VERSION 5.7 ;
  NOWIREEXTENSIONATPIN ON ;
  DIVIDERCHAR "/" ;
  BUSBITCHARS "[]" ;
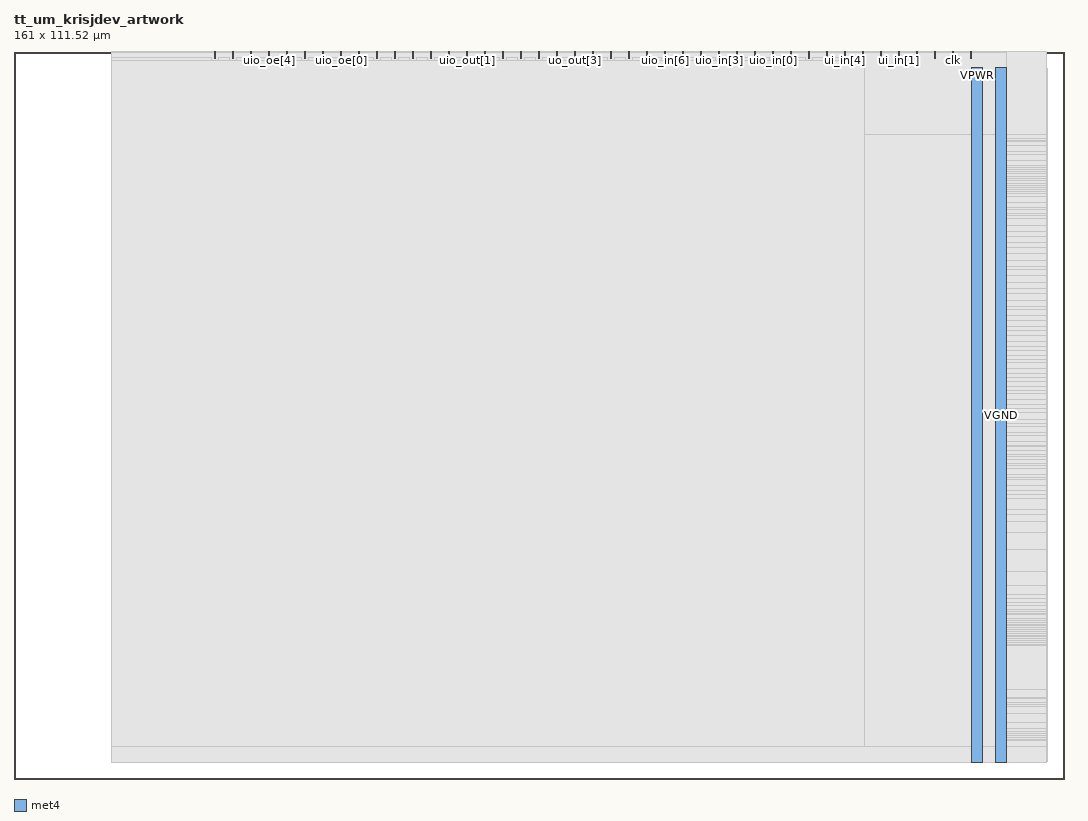
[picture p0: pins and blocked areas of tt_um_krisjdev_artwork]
MACRO tt_um_krisjdev_artwork
  CLASS BLOCK ;
  FOREIGN tt_um_krisjdev_artwork ;
  ORIGIN 0.000 0.000 ;
  SIZE 161.000 BY 111.520 ;
  PIN VGND
    DIRECTION INOUT ;
    USE GROUND ;
    PORT
      LAYER met4 ;
        RECT 150.540 2.480 152.140 109.040 ;
    END
  END VGND
  PIN VPWR
    DIRECTION INOUT ;
    USE POWER ;
    PORT
      LAYER met4 ;
        RECT 146.860 2.480 148.460 109.040 ;
    END
  END VPWR
  PIN clk
    DIRECTION INPUT ;
    USE SIGNAL ;
    PORT
      LAYER met4 ;
        RECT 143.830 110.520 144.130 111.520 ;
    END
  END clk
  PIN ena
    DIRECTION INPUT ;
    USE SIGNAL ;
    PORT
      LAYER met4 ;
        RECT 146.590 110.520 146.890 111.520 ;
    END
  END ena
  PIN rst_n
    DIRECTION INPUT ;
    USE SIGNAL ;
    PORT
      LAYER met4 ;
        RECT 141.070 110.520 141.370 111.520 ;
    END
  END rst_n
  PIN ui_in[0]
    DIRECTION INPUT ;
    USE SIGNAL ;
    PORT
      LAYER met4 ;
        RECT 138.310 110.520 138.610 111.520 ;
    END
  END ui_in[0]
  PIN ui_in[1]
    DIRECTION INPUT ;
    USE SIGNAL ;
    PORT
      LAYER met4 ;
        RECT 135.550 110.520 135.850 111.520 ;
    END
  END ui_in[1]
  PIN ui_in[2]
    DIRECTION INPUT ;
    USE SIGNAL ;
    PORT
      LAYER met4 ;
        RECT 132.790 110.520 133.090 111.520 ;
    END
  END ui_in[2]
  PIN ui_in[3]
    DIRECTION INPUT ;
    USE SIGNAL ;
    PORT
      LAYER met4 ;
        RECT 130.030 110.520 130.330 111.520 ;
    END
  END ui_in[3]
  PIN ui_in[4]
    DIRECTION INPUT ;
    USE SIGNAL ;
    PORT
      LAYER met4 ;
        RECT 127.270 110.520 127.570 111.520 ;
    END
  END ui_in[4]
  PIN ui_in[5]
    DIRECTION INPUT ;
    USE SIGNAL ;
    PORT
      LAYER met4 ;
        RECT 124.510 110.520 124.810 111.520 ;
    END
  END ui_in[5]
  PIN ui_in[6]
    DIRECTION INPUT ;
    USE SIGNAL ;
    PORT
      LAYER met4 ;
        RECT 121.750 110.520 122.050 111.520 ;
    END
  END ui_in[6]
  PIN ui_in[7]
    DIRECTION INPUT ;
    USE SIGNAL ;
    PORT
      LAYER met4 ;
        RECT 118.990 110.520 119.290 111.520 ;
    END
  END ui_in[7]
  PIN uio_in[0]
    DIRECTION INPUT ;
    USE SIGNAL ;
    PORT
      LAYER met4 ;
        RECT 116.230 110.520 116.530 111.520 ;
    END
  END uio_in[0]
  PIN uio_in[1]
    DIRECTION INPUT ;
    USE SIGNAL ;
    PORT
      LAYER met4 ;
        RECT 113.470 110.520 113.770 111.520 ;
    END
  END uio_in[1]
  PIN uio_in[2]
    DIRECTION INPUT ;
    USE SIGNAL ;
    PORT
      LAYER met4 ;
        RECT 110.710 110.520 111.010 111.520 ;
    END
  END uio_in[2]
  PIN uio_in[3]
    DIRECTION INPUT ;
    USE SIGNAL ;
    PORT
      LAYER met4 ;
        RECT 107.950 110.520 108.250 111.520 ;
    END
  END uio_in[3]
  PIN uio_in[4]
    DIRECTION INPUT ;
    USE SIGNAL ;
    PORT
      LAYER met4 ;
        RECT 105.190 110.520 105.490 111.520 ;
    END
  END uio_in[4]
  PIN uio_in[5]
    DIRECTION INPUT ;
    USE SIGNAL ;
    PORT
      LAYER met4 ;
        RECT 102.430 110.520 102.730 111.520 ;
    END
  END uio_in[5]
  PIN uio_in[6]
    DIRECTION INPUT ;
    USE SIGNAL ;
    PORT
      LAYER met4 ;
        RECT 99.670 110.520 99.970 111.520 ;
    END
  END uio_in[6]
  PIN uio_in[7]
    DIRECTION INPUT ;
    USE SIGNAL ;
    PORT
      LAYER met4 ;
        RECT 96.910 110.520 97.210 111.520 ;
    END
  END uio_in[7]
  PIN uio_oe[0]
    DIRECTION OUTPUT ;
    USE SIGNAL ;
    PORT
      LAYER met4 ;
        RECT 49.990 110.520 50.290 111.520 ;
    END
  END uio_oe[0]
  PIN uio_oe[1]
    DIRECTION OUTPUT ;
    USE SIGNAL ;
    PORT
      LAYER met4 ;
        RECT 47.230 110.520 47.530 111.520 ;
    END
  END uio_oe[1]
  PIN uio_oe[2]
    DIRECTION OUTPUT ;
    USE SIGNAL ;
    PORT
      LAYER met4 ;
        RECT 44.470 110.520 44.770 111.520 ;
    END
  END uio_oe[2]
  PIN uio_oe[3]
    DIRECTION OUTPUT ;
    USE SIGNAL ;
    PORT
      LAYER met4 ;
        RECT 41.710 110.520 42.010 111.520 ;
    END
  END uio_oe[3]
  PIN uio_oe[4]
    DIRECTION OUTPUT ;
    USE SIGNAL ;
    PORT
      LAYER met4 ;
        RECT 38.950 110.520 39.250 111.520 ;
    END
  END uio_oe[4]
  PIN uio_oe[5]
    DIRECTION OUTPUT ;
    USE SIGNAL ;
    PORT
      LAYER met4 ;
        RECT 36.190 110.520 36.490 111.520 ;
    END
  END uio_oe[5]
  PIN uio_oe[6]
    DIRECTION OUTPUT ;
    USE SIGNAL ;
    PORT
      LAYER met4 ;
        RECT 33.430 110.520 33.730 111.520 ;
    END
  END uio_oe[6]
  PIN uio_oe[7]
    DIRECTION OUTPUT ;
    USE SIGNAL ;
    PORT
      LAYER met4 ;
        RECT 30.670 110.520 30.970 111.520 ;
    END
  END uio_oe[7]
  PIN uio_out[0]
    DIRECTION OUTPUT ;
    USE SIGNAL ;
    PORT
      LAYER met4 ;
        RECT 72.070 110.520 72.370 111.520 ;
    END
  END uio_out[0]
  PIN uio_out[1]
    DIRECTION OUTPUT ;
    USE SIGNAL ;
    PORT
      LAYER met4 ;
        RECT 69.310 110.520 69.610 111.520 ;
    END
  END uio_out[1]
  PIN uio_out[2]
    DIRECTION OUTPUT ;
    USE SIGNAL ;
    PORT
      LAYER met4 ;
        RECT 66.550 110.520 66.850 111.520 ;
    END
  END uio_out[2]
  PIN uio_out[3]
    DIRECTION OUTPUT ;
    USE SIGNAL ;
    PORT
      LAYER met4 ;
        RECT 63.790 110.520 64.090 111.520 ;
    END
  END uio_out[3]
  PIN uio_out[4]
    DIRECTION OUTPUT ;
    USE SIGNAL ;
    PORT
      LAYER met4 ;
        RECT 61.030 110.520 61.330 111.520 ;
    END
  END uio_out[4]
  PIN uio_out[5]
    DIRECTION OUTPUT ;
    USE SIGNAL ;
    PORT
      LAYER met4 ;
        RECT 58.270 110.520 58.570 111.520 ;
    END
  END uio_out[5]
  PIN uio_out[6]
    DIRECTION OUTPUT ;
    USE SIGNAL ;
    PORT
      LAYER met4 ;
        RECT 55.510 110.520 55.810 111.520 ;
    END
  END uio_out[6]
  PIN uio_out[7]
    DIRECTION OUTPUT ;
    USE SIGNAL ;
    PORT
      LAYER met4 ;
        RECT 52.750 110.520 53.050 111.520 ;
    END
  END uio_out[7]
  PIN uo_out[0]
    DIRECTION OUTPUT ;
    USE SIGNAL ;
    PORT
      LAYER met4 ;
        RECT 94.150 110.520 94.450 111.520 ;
    END
  END uo_out[0]
  PIN uo_out[1]
    DIRECTION OUTPUT ;
    USE SIGNAL ;
    PORT
      LAYER met4 ;
        RECT 91.390 110.520 91.690 111.520 ;
    END
  END uo_out[1]
  PIN uo_out[2]
    DIRECTION OUTPUT ;
    USE SIGNAL ;
    PORT
      LAYER met4 ;
        RECT 88.630 110.520 88.930 111.520 ;
    END
  END uo_out[2]
  PIN uo_out[3]
    DIRECTION OUTPUT ;
    USE SIGNAL ;
    PORT
      LAYER met4 ;
        RECT 85.870 110.520 86.170 111.520 ;
    END
  END uo_out[3]
  PIN uo_out[4]
    DIRECTION OUTPUT ;
    USE SIGNAL ;
    PORT
      LAYER met4 ;
        RECT 83.110 110.520 83.410 111.520 ;
    END
  END uo_out[4]
  PIN uo_out[5]
    DIRECTION OUTPUT ;
    USE SIGNAL ;
    PORT
      LAYER met4 ;
        RECT 80.350 110.520 80.650 111.520 ;
    END
  END uo_out[5]
  PIN uo_out[6]
    DIRECTION OUTPUT ;
    USE SIGNAL ;
    PORT
      LAYER met4 ;
        RECT 77.590 110.520 77.890 111.520 ;
    END
  END uo_out[6]
  PIN uo_out[7]
    DIRECTION OUTPUT ;
    USE SIGNAL ;
    PORT
      LAYER met4 ;
        RECT 74.830 110.520 75.130 111.520 ;
    END
  END uo_out[7]
  OBS
      LAYER nwell ;
        RECT 140.570 2.635 158.430 108.990 ;
      LAYER li1 ;
        RECT 140.760 2.635 158.240 108.885 ;
      LAYER met1 ;
        RECT 15.000 98.800 158.240 111.480 ;
      LAYER met1 ;
        RECT 15.000 98.240 130.360 98.800 ;
      LAYER met1 ;
        RECT 130.360 98.240 158.240 98.800 ;
      LAYER met1 ;
        RECT 15.000 97.960 111.880 98.240 ;
      LAYER met1 ;
        RECT 111.880 97.960 158.240 98.240 ;
      LAYER met1 ;
        RECT 15.000 97.680 111.600 97.960 ;
      LAYER met1 ;
        RECT 111.600 97.680 158.240 97.960 ;
      LAYER met1 ;
        RECT 15.000 97.120 111.320 97.680 ;
      LAYER met1 ;
        RECT 111.320 97.120 158.240 97.680 ;
      LAYER met1 ;
        RECT 15.000 96.280 111.040 97.120 ;
      LAYER met1 ;
        RECT 111.040 96.280 158.240 97.120 ;
      LAYER met1 ;
        RECT 15.000 95.720 110.760 96.280 ;
      LAYER met1 ;
        RECT 110.760 95.720 158.240 96.280 ;
      LAYER met1 ;
        RECT 15.000 94.880 110.480 95.720 ;
      LAYER met1 ;
        RECT 110.480 94.880 158.240 95.720 ;
      LAYER met1 ;
        RECT 15.000 94.040 110.200 94.880 ;
      LAYER met1 ;
        RECT 110.200 94.040 158.240 94.880 ;
      LAYER met1 ;
        RECT 15.000 93.760 109.920 94.040 ;
      LAYER met1 ;
        RECT 109.920 93.760 158.240 94.040 ;
      LAYER met1 ;
        RECT 15.000 93.480 90.040 93.760 ;
      LAYER met1 ;
        RECT 90.040 93.480 158.240 93.760 ;
      LAYER met1 ;
        RECT 15.000 93.200 89.760 93.480 ;
      LAYER met1 ;
        RECT 89.760 93.200 158.240 93.480 ;
      LAYER met1 ;
        RECT 15.000 92.920 89.200 93.200 ;
      LAYER met1 ;
        RECT 89.200 92.920 158.240 93.200 ;
      LAYER met1 ;
        RECT 15.000 92.360 88.640 92.920 ;
      LAYER met1 ;
        RECT 88.640 92.360 158.240 92.920 ;
      LAYER met1 ;
        RECT 15.000 92.080 88.360 92.360 ;
      LAYER met1 ;
        RECT 88.360 92.080 158.240 92.360 ;
      LAYER met1 ;
        RECT 15.000 91.800 88.080 92.080 ;
      LAYER met1 ;
        RECT 88.080 91.800 158.240 92.080 ;
      LAYER met1 ;
        RECT 15.000 91.240 45.800 91.800 ;
      LAYER met1 ;
        RECT 45.800 91.240 158.240 91.800 ;
      LAYER met1 ;
        RECT 15.000 90.960 40.760 91.240 ;
      LAYER met1 ;
        RECT 40.760 90.960 158.240 91.240 ;
      LAYER met1 ;
        RECT 15.000 90.680 39.920 90.960 ;
      LAYER met1 ;
        RECT 39.920 90.680 158.240 90.960 ;
      LAYER met1 ;
        RECT 15.000 90.400 39.080 90.680 ;
      LAYER met1 ;
        RECT 39.080 90.400 158.240 90.680 ;
      LAYER met1 ;
        RECT 15.000 90.120 38.520 90.400 ;
      LAYER met1 ;
        RECT 38.520 90.120 158.240 90.400 ;
      LAYER met1 ;
        RECT 15.000 89.840 36.280 90.120 ;
      LAYER met1 ;
        RECT 36.280 89.840 158.240 90.120 ;
      LAYER met1 ;
        RECT 15.000 89.280 36.000 89.840 ;
      LAYER met1 ;
        RECT 36.000 89.280 158.240 89.840 ;
      LAYER met1 ;
        RECT 15.000 88.440 35.720 89.280 ;
      LAYER met1 ;
        RECT 35.720 88.440 158.240 89.280 ;
      LAYER met1 ;
        RECT 15.000 87.600 35.440 88.440 ;
      LAYER met1 ;
        RECT 35.440 87.600 158.240 88.440 ;
      LAYER met1 ;
        RECT 15.000 87.320 35.160 87.600 ;
      LAYER met1 ;
        RECT 35.160 87.320 158.240 87.600 ;
      LAYER met1 ;
        RECT 15.000 86.760 34.880 87.320 ;
      LAYER met1 ;
        RECT 34.880 86.760 158.240 87.320 ;
      LAYER met1 ;
        RECT 15.000 86.480 34.600 86.760 ;
      LAYER met1 ;
        RECT 34.600 86.480 158.240 86.760 ;
      LAYER met1 ;
        RECT 15.000 85.920 34.320 86.480 ;
      LAYER met1 ;
        RECT 34.320 85.920 158.240 86.480 ;
      LAYER met1 ;
        RECT 15.000 84.800 34.040 85.920 ;
      LAYER met1 ;
        RECT 34.040 84.800 158.240 85.920 ;
      LAYER met1 ;
        RECT 15.000 83.960 33.760 84.800 ;
      LAYER met1 ;
        RECT 33.760 83.960 158.240 84.800 ;
      LAYER met1 ;
        RECT 15.000 83.120 33.480 83.960 ;
      LAYER met1 ;
        RECT 33.480 83.120 158.240 83.960 ;
      LAYER met1 ;
        RECT 15.000 82.280 33.200 83.120 ;
      LAYER met1 ;
        RECT 33.200 82.280 158.240 83.120 ;
      LAYER met1 ;
        RECT 15.000 81.440 32.920 82.280 ;
      LAYER met1 ;
        RECT 32.920 81.440 158.240 82.280 ;
      LAYER met1 ;
        RECT 15.000 80.600 32.640 81.440 ;
      LAYER met1 ;
        RECT 32.640 80.600 158.240 81.440 ;
      LAYER met1 ;
        RECT 15.000 79.480 32.360 80.600 ;
      LAYER met1 ;
        RECT 32.360 79.480 158.240 80.600 ;
      LAYER met1 ;
        RECT 15.000 78.640 32.080 79.480 ;
      LAYER met1 ;
        RECT 32.080 78.640 158.240 79.480 ;
      LAYER met1 ;
        RECT 15.000 78.080 31.800 78.640 ;
      LAYER met1 ;
        RECT 31.800 78.080 158.240 78.640 ;
      LAYER met1 ;
        RECT 15.000 77.240 31.520 78.080 ;
      LAYER met1 ;
        RECT 31.520 77.240 158.240 78.080 ;
      LAYER met1 ;
        RECT 15.000 76.120 31.240 77.240 ;
      LAYER met1 ;
        RECT 31.240 76.120 158.240 77.240 ;
      LAYER met1 ;
        RECT 15.000 75.280 30.960 76.120 ;
      LAYER met1 ;
        RECT 30.960 75.280 158.240 76.120 ;
      LAYER met1 ;
        RECT 15.000 74.440 30.680 75.280 ;
      LAYER met1 ;
        RECT 30.680 74.440 158.240 75.280 ;
      LAYER met1 ;
        RECT 15.000 73.320 30.400 74.440 ;
      LAYER met1 ;
        RECT 30.400 73.320 158.240 74.440 ;
      LAYER met1 ;
        RECT 15.000 72.480 30.120 73.320 ;
      LAYER met1 ;
        RECT 30.120 72.480 158.240 73.320 ;
      LAYER met1 ;
        RECT 15.000 71.920 29.840 72.480 ;
      LAYER met1 ;
        RECT 29.840 71.920 158.240 72.480 ;
      LAYER met1 ;
        RECT 15.000 71.080 29.560 71.920 ;
      LAYER met1 ;
        RECT 29.560 71.080 158.240 71.920 ;
      LAYER met1 ;
        RECT 15.000 70.240 29.280 71.080 ;
      LAYER met1 ;
        RECT 29.280 70.240 158.240 71.080 ;
      LAYER met1 ;
        RECT 15.000 69.400 29.000 70.240 ;
      LAYER met1 ;
        RECT 29.000 69.400 158.240 70.240 ;
      LAYER met1 ;
        RECT 15.000 68.840 28.720 69.400 ;
      LAYER met1 ;
        RECT 28.720 68.840 158.240 69.400 ;
      LAYER met1 ;
        RECT 15.000 68.000 28.440 68.840 ;
      LAYER met1 ;
        RECT 28.440 68.000 158.240 68.840 ;
      LAYER met1 ;
        RECT 15.000 67.160 28.160 68.000 ;
      LAYER met1 ;
        RECT 28.160 67.160 158.240 68.000 ;
      LAYER met1 ;
        RECT 15.000 66.320 27.880 67.160 ;
      LAYER met1 ;
        RECT 27.880 66.320 158.240 67.160 ;
      LAYER met1 ;
        RECT 15.000 65.760 27.600 66.320 ;
      LAYER met1 ;
        RECT 27.600 65.760 158.240 66.320 ;
      LAYER met1 ;
        RECT 15.000 64.920 27.320 65.760 ;
      LAYER met1 ;
        RECT 27.320 64.920 158.240 65.760 ;
      LAYER met1 ;
        RECT 15.000 64.360 27.040 64.920 ;
      LAYER met1 ;
        RECT 27.040 64.360 158.240 64.920 ;
      LAYER met1 ;
        RECT 15.000 63.800 26.760 64.360 ;
      LAYER met1 ;
        RECT 26.760 63.800 158.240 64.360 ;
      LAYER met1 ;
        RECT 15.000 62.960 26.480 63.800 ;
      LAYER met1 ;
        RECT 26.480 62.960 158.240 63.800 ;
      LAYER met1 ;
        RECT 15.000 62.120 26.200 62.960 ;
      LAYER met1 ;
        RECT 26.200 62.120 158.240 62.960 ;
      LAYER met1 ;
        RECT 15.000 61.560 25.920 62.120 ;
      LAYER met1 ;
        RECT 25.920 61.560 158.240 62.120 ;
      LAYER met1 ;
        RECT 15.000 61.000 25.640 61.560 ;
      LAYER met1 ;
        RECT 25.640 61.000 158.240 61.560 ;
      LAYER met1 ;
        RECT 15.000 60.160 25.360 61.000 ;
      LAYER met1 ;
        RECT 25.360 60.160 158.240 61.000 ;
      LAYER met1 ;
        RECT 15.000 59.600 25.080 60.160 ;
      LAYER met1 ;
        RECT 25.080 59.600 158.240 60.160 ;
      LAYER met1 ;
        RECT 15.000 59.040 24.800 59.600 ;
      LAYER met1 ;
        RECT 24.800 59.040 158.240 59.600 ;
      LAYER met1 ;
        RECT 15.000 58.200 24.520 59.040 ;
      LAYER met1 ;
        RECT 24.520 58.200 158.240 59.040 ;
      LAYER met1 ;
        RECT 15.000 57.360 24.240 58.200 ;
      LAYER met1 ;
        RECT 24.240 57.360 158.240 58.200 ;
      LAYER met1 ;
        RECT 15.000 56.800 23.960 57.360 ;
      LAYER met1 ;
        RECT 23.960 56.800 158.240 57.360 ;
      LAYER met1 ;
        RECT 15.000 56.240 23.680 56.800 ;
      LAYER met1 ;
        RECT 23.680 56.240 158.240 56.800 ;
      LAYER met1 ;
        RECT 15.000 55.120 23.400 56.240 ;
      LAYER met1 ;
        RECT 23.400 55.120 158.240 56.240 ;
      LAYER met1 ;
        RECT 15.000 54.560 23.120 55.120 ;
      LAYER met1 ;
        RECT 23.120 54.560 158.240 55.120 ;
      LAYER met1 ;
        RECT 15.000 54.000 22.840 54.560 ;
      LAYER met1 ;
        RECT 22.840 54.000 158.240 54.560 ;
      LAYER met1 ;
        RECT 15.000 53.160 22.560 54.000 ;
      LAYER met1 ;
        RECT 22.560 53.160 158.240 54.000 ;
      LAYER met1 ;
        RECT 15.000 52.600 22.280 53.160 ;
      LAYER met1 ;
        RECT 22.280 52.600 158.240 53.160 ;
      LAYER met1 ;
        RECT 15.000 51.760 22.000 52.600 ;
      LAYER met1 ;
        RECT 22.000 51.760 158.240 52.600 ;
      LAYER met1 ;
        RECT 15.000 51.200 21.720 51.760 ;
      LAYER met1 ;
        RECT 21.720 51.200 158.240 51.760 ;
      LAYER met1 ;
        RECT 15.000 50.920 21.440 51.200 ;
      LAYER met1 ;
        RECT 21.440 50.920 158.240 51.200 ;
      LAYER met1 ;
        RECT 15.000 50.360 21.160 50.920 ;
      LAYER met1 ;
        RECT 21.160 50.360 158.240 50.920 ;
      LAYER met1 ;
        RECT 15.000 49.800 20.880 50.360 ;
      LAYER met1 ;
        RECT 20.880 49.800 158.240 50.360 ;
      LAYER met1 ;
        RECT 15.000 49.520 20.600 49.800 ;
      LAYER met1 ;
        RECT 20.600 49.520 158.240 49.800 ;
      LAYER met1 ;
        RECT 15.000 48.960 20.320 49.520 ;
      LAYER met1 ;
        RECT 20.320 48.960 158.240 49.520 ;
      LAYER met1 ;
        RECT 15.000 48.400 20.040 48.960 ;
      LAYER met1 ;
        RECT 20.040 48.400 158.240 48.960 ;
      LAYER met1 ;
        RECT 15.000 48.120 19.760 48.400 ;
      LAYER met1 ;
        RECT 19.760 48.120 158.240 48.400 ;
      LAYER met1 ;
        RECT 15.000 47.560 19.480 48.120 ;
      LAYER met1 ;
        RECT 19.480 47.560 158.240 48.120 ;
      LAYER met1 ;
        RECT 15.000 46.720 19.200 47.560 ;
      LAYER met1 ;
        RECT 19.200 46.720 158.240 47.560 ;
      LAYER met1 ;
        RECT 15.000 46.160 18.920 46.720 ;
      LAYER met1 ;
        RECT 18.920 46.160 158.240 46.720 ;
      LAYER met1 ;
        RECT 15.000 45.880 18.640 46.160 ;
      LAYER met1 ;
        RECT 18.640 45.880 158.240 46.160 ;
      LAYER met1 ;
        RECT 15.000 45.040 18.360 45.880 ;
      LAYER met1 ;
        RECT 18.360 45.040 158.240 45.880 ;
      LAYER met1 ;
        RECT 15.000 44.200 18.080 45.040 ;
      LAYER met1 ;
        RECT 18.080 44.200 158.240 45.040 ;
      LAYER met1 ;
        RECT 15.000 43.640 17.800 44.200 ;
      LAYER met1 ;
        RECT 17.800 43.640 158.240 44.200 ;
      LAYER met1 ;
        RECT 15.000 43.080 17.520 43.640 ;
      LAYER met1 ;
        RECT 17.520 43.080 158.240 43.640 ;
      LAYER met1 ;
        RECT 15.000 41.400 17.240 43.080 ;
      LAYER met1 ;
        RECT 17.240 41.400 158.240 43.080 ;
      LAYER met1 ;
        RECT 15.000 40.560 16.960 41.400 ;
      LAYER met1 ;
        RECT 16.960 40.560 158.240 41.400 ;
      LAYER met1 ;
        RECT 15.000 39.440 16.680 40.560 ;
      LAYER met1 ;
        RECT 16.680 39.440 158.240 40.560 ;
      LAYER met1 ;
        RECT 15.000 37.760 16.400 39.440 ;
      LAYER met1 ;
        RECT 16.400 37.760 158.240 39.440 ;
      LAYER met1 ;
        RECT 15.000 35.240 16.120 37.760 ;
      LAYER met1 ;
        RECT 16.120 35.240 158.240 37.760 ;
      LAYER met1 ;
        RECT 15.000 31.880 15.840 35.240 ;
      LAYER met1 ;
        RECT 15.840 31.880 158.240 35.240 ;
      LAYER met1 ;
        RECT 15.000 29.640 16.120 31.880 ;
      LAYER met1 ;
        RECT 16.120 29.640 158.240 31.880 ;
      LAYER met1 ;
        RECT 15.000 28.240 16.400 29.640 ;
      LAYER met1 ;
        RECT 16.400 28.240 158.240 29.640 ;
      LAYER met1 ;
        RECT 15.000 27.680 16.680 28.240 ;
      LAYER met1 ;
        RECT 16.680 27.680 158.240 28.240 ;
      LAYER met1 ;
        RECT 15.000 27.120 16.960 27.680 ;
      LAYER met1 ;
        RECT 16.960 27.120 158.240 27.680 ;
      LAYER met1 ;
        RECT 15.000 26.560 17.240 27.120 ;
      LAYER met1 ;
        RECT 17.240 26.560 158.240 27.120 ;
      LAYER met1 ;
        RECT 15.000 26.000 17.520 26.560 ;
      LAYER met1 ;
        RECT 17.520 26.000 158.240 26.560 ;
      LAYER met1 ;
        RECT 15.000 25.720 17.800 26.000 ;
      LAYER met1 ;
        RECT 17.800 25.720 158.240 26.000 ;
      LAYER met1 ;
        RECT 15.000 25.440 18.080 25.720 ;
      LAYER met1 ;
        RECT 18.080 25.440 158.240 25.720 ;
      LAYER met1 ;
        RECT 15.000 25.160 18.360 25.440 ;
      LAYER met1 ;
        RECT 18.360 25.160 158.240 25.440 ;
      LAYER met1 ;
        RECT 15.000 24.600 18.640 25.160 ;
      LAYER met1 ;
        RECT 18.640 24.600 158.240 25.160 ;
      LAYER met1 ;
        RECT 15.000 24.320 18.920 24.600 ;
      LAYER met1 ;
        RECT 18.920 24.320 158.240 24.600 ;
      LAYER met1 ;
        RECT 15.000 24.040 19.200 24.320 ;
      LAYER met1 ;
        RECT 19.200 24.040 158.240 24.320 ;
      LAYER met1 ;
        RECT 15.000 23.760 19.480 24.040 ;
      LAYER met1 ;
        RECT 19.480 23.760 158.240 24.040 ;
      LAYER met1 ;
        RECT 15.000 23.480 19.760 23.760 ;
      LAYER met1 ;
        RECT 19.760 23.480 158.240 23.760 ;
      LAYER met1 ;
        RECT 15.000 23.200 20.040 23.480 ;
      LAYER met1 ;
        RECT 20.040 23.200 158.240 23.480 ;
      LAYER met1 ;
        RECT 15.000 22.920 20.320 23.200 ;
      LAYER met1 ;
        RECT 20.320 22.920 158.240 23.200 ;
      LAYER met1 ;
        RECT 15.000 22.640 20.600 22.920 ;
      LAYER met1 ;
        RECT 20.600 22.640 158.240 22.920 ;
      LAYER met1 ;
        RECT 15.000 22.360 21.160 22.640 ;
      LAYER met1 ;
        RECT 21.160 22.360 158.240 22.640 ;
      LAYER met1 ;
        RECT 15.000 22.080 21.440 22.360 ;
      LAYER met1 ;
        RECT 21.440 22.080 158.240 22.360 ;
      LAYER met1 ;
        RECT 15.000 21.800 21.720 22.080 ;
      LAYER met1 ;
        RECT 21.720 21.800 158.240 22.080 ;
      LAYER met1 ;
        RECT 15.000 21.520 22.000 21.800 ;
      LAYER met1 ;
        RECT 22.000 21.520 158.240 21.800 ;
      LAYER met1 ;
        RECT 15.000 21.240 22.280 21.520 ;
      LAYER met1 ;
        RECT 22.280 21.240 158.240 21.520 ;
      LAYER met1 ;
        RECT 15.000 20.960 22.840 21.240 ;
      LAYER met1 ;
        RECT 22.840 20.960 158.240 21.240 ;
      LAYER met1 ;
        RECT 15.000 20.680 23.400 20.960 ;
      LAYER met1 ;
        RECT 23.400 20.680 158.240 20.960 ;
      LAYER met1 ;
        RECT 15.000 20.400 24.800 20.680 ;
      LAYER met1 ;
        RECT 24.800 20.400 158.240 20.680 ;
      LAYER met1 ;
        RECT 15.000 13.680 26.480 20.400 ;
      LAYER met1 ;
        RECT 26.480 13.680 158.240 20.400 ;
      LAYER met1 ;
        RECT 15.000 12.560 26.760 13.680 ;
      LAYER met1 ;
        RECT 26.760 12.560 158.240 13.680 ;
      LAYER met1 ;
        RECT 15.000 12.280 27.040 12.560 ;
      LAYER met1 ;
        RECT 27.040 12.280 158.240 12.560 ;
      LAYER met1 ;
        RECT 15.000 11.720 27.320 12.280 ;
      LAYER met1 ;
        RECT 27.320 11.720 158.240 12.280 ;
      LAYER met1 ;
        RECT 15.000 11.440 28.160 11.720 ;
      LAYER met1 ;
        RECT 28.160 11.440 158.240 11.720 ;
      LAYER met1 ;
        RECT 15.000 11.160 81.640 11.440 ;
      LAYER met1 ;
        RECT 81.640 11.160 158.240 11.440 ;
      LAYER met1 ;
        RECT 15.000 10.040 81.360 11.160 ;
      LAYER met1 ;
        RECT 81.360 10.040 158.240 11.160 ;
      LAYER met1 ;
        RECT 15.000 8.640 81.080 10.040 ;
      LAYER met1 ;
        RECT 81.080 8.640 158.240 10.040 ;
      LAYER met1 ;
        RECT 15.000 7.800 81.360 8.640 ;
      LAYER met1 ;
        RECT 81.360 7.800 158.240 8.640 ;
      LAYER met1 ;
        RECT 15.000 7.240 81.640 7.800 ;
      LAYER met1 ;
        RECT 81.640 7.240 158.240 7.800 ;
      LAYER met1 ;
        RECT 15.000 6.960 81.920 7.240 ;
      LAYER met1 ;
        RECT 81.920 6.960 158.240 7.240 ;
      LAYER met1 ;
        RECT 15.000 6.680 82.480 6.960 ;
      LAYER met1 ;
        RECT 82.480 6.680 158.240 6.960 ;
      LAYER met1 ;
        RECT 15.000 6.400 83.320 6.680 ;
      LAYER met1 ;
        RECT 83.320 6.400 158.240 6.680 ;
      LAYER met1 ;
        RECT 15.000 6.120 120.560 6.400 ;
      LAYER met1 ;
        RECT 120.560 6.120 158.240 6.400 ;
      LAYER met1 ;
        RECT 15.000 5.840 121.120 6.120 ;
      LAYER met1 ;
        RECT 121.120 5.840 158.240 6.120 ;
      LAYER met1 ;
        RECT 15.000 5.000 130.360 5.840 ;
      LAYER met1 ;
        RECT 130.360 5.000 158.240 5.840 ;
        RECT 15.000 2.480 158.240 5.000 ;
      LAYER met2 ;
        RECT 15.000 98.800 152.110 111.510 ;
      LAYER met2 ;
        RECT 15.000 98.240 130.360 98.800 ;
      LAYER met2 ;
        RECT 130.360 98.240 152.110 98.800 ;
      LAYER met2 ;
        RECT 15.000 97.960 111.880 98.240 ;
      LAYER met2 ;
        RECT 111.880 97.960 152.110 98.240 ;
      LAYER met2 ;
        RECT 15.000 97.680 111.600 97.960 ;
      LAYER met2 ;
        RECT 111.600 97.680 152.110 97.960 ;
      LAYER met2 ;
        RECT 15.000 97.120 111.320 97.680 ;
      LAYER met2 ;
        RECT 111.320 97.120 152.110 97.680 ;
      LAYER met2 ;
        RECT 15.000 96.280 111.040 97.120 ;
      LAYER met2 ;
        RECT 111.040 96.280 152.110 97.120 ;
      LAYER met2 ;
        RECT 15.000 95.720 110.760 96.280 ;
      LAYER met2 ;
        RECT 110.760 95.720 152.110 96.280 ;
      LAYER met2 ;
        RECT 15.000 94.880 110.480 95.720 ;
      LAYER met2 ;
        RECT 110.480 94.880 152.110 95.720 ;
      LAYER met2 ;
        RECT 15.000 94.040 110.200 94.880 ;
      LAYER met2 ;
        RECT 110.200 94.040 152.110 94.880 ;
      LAYER met2 ;
        RECT 15.000 93.760 109.920 94.040 ;
      LAYER met2 ;
        RECT 109.920 93.760 152.110 94.040 ;
      LAYER met2 ;
        RECT 15.000 93.480 90.040 93.760 ;
      LAYER met2 ;
        RECT 90.040 93.480 152.110 93.760 ;
      LAYER met2 ;
        RECT 15.000 93.200 89.760 93.480 ;
      LAYER met2 ;
        RECT 89.760 93.200 152.110 93.480 ;
      LAYER met2 ;
        RECT 15.000 92.920 89.200 93.200 ;
      LAYER met2 ;
        RECT 89.200 92.920 152.110 93.200 ;
      LAYER met2 ;
        RECT 15.000 92.360 88.640 92.920 ;
      LAYER met2 ;
        RECT 88.640 92.360 152.110 92.920 ;
      LAYER met2 ;
        RECT 15.000 92.080 88.360 92.360 ;
      LAYER met2 ;
        RECT 88.360 92.080 152.110 92.360 ;
      LAYER met2 ;
        RECT 15.000 91.800 88.080 92.080 ;
      LAYER met2 ;
        RECT 88.080 91.800 152.110 92.080 ;
      LAYER met2 ;
        RECT 15.000 91.240 45.800 91.800 ;
      LAYER met2 ;
        RECT 45.800 91.240 152.110 91.800 ;
      LAYER met2 ;
        RECT 15.000 90.960 40.760 91.240 ;
      LAYER met2 ;
        RECT 40.760 90.960 152.110 91.240 ;
      LAYER met2 ;
        RECT 15.000 90.680 39.920 90.960 ;
      LAYER met2 ;
        RECT 39.920 90.680 152.110 90.960 ;
      LAYER met2 ;
        RECT 15.000 90.400 39.080 90.680 ;
      LAYER met2 ;
        RECT 39.080 90.400 152.110 90.680 ;
      LAYER met2 ;
        RECT 15.000 90.120 38.520 90.400 ;
      LAYER met2 ;
        RECT 38.520 90.120 152.110 90.400 ;
      LAYER met2 ;
        RECT 15.000 89.840 36.280 90.120 ;
      LAYER met2 ;
        RECT 36.280 89.840 152.110 90.120 ;
      LAYER met2 ;
        RECT 15.000 89.280 36.000 89.840 ;
      LAYER met2 ;
        RECT 36.000 89.280 152.110 89.840 ;
      LAYER met2 ;
        RECT 15.000 88.440 35.720 89.280 ;
      LAYER met2 ;
        RECT 35.720 88.440 152.110 89.280 ;
      LAYER met2 ;
        RECT 15.000 87.600 35.440 88.440 ;
      LAYER met2 ;
        RECT 35.440 87.600 152.110 88.440 ;
      LAYER met2 ;
        RECT 15.000 87.320 35.160 87.600 ;
      LAYER met2 ;
        RECT 35.160 87.320 152.110 87.600 ;
      LAYER met2 ;
        RECT 15.000 86.760 34.880 87.320 ;
      LAYER met2 ;
        RECT 34.880 86.760 152.110 87.320 ;
      LAYER met2 ;
        RECT 15.000 86.480 34.600 86.760 ;
      LAYER met2 ;
        RECT 34.600 86.480 152.110 86.760 ;
      LAYER met2 ;
        RECT 15.000 85.920 34.320 86.480 ;
      LAYER met2 ;
        RECT 34.320 85.920 152.110 86.480 ;
      LAYER met2 ;
        RECT 15.000 84.800 34.040 85.920 ;
      LAYER met2 ;
        RECT 34.040 84.800 152.110 85.920 ;
      LAYER met2 ;
        RECT 15.000 83.960 33.760 84.800 ;
      LAYER met2 ;
        RECT 33.760 83.960 152.110 84.800 ;
      LAYER met2 ;
        RECT 15.000 83.120 33.480 83.960 ;
      LAYER met2 ;
        RECT 33.480 83.120 152.110 83.960 ;
      LAYER met2 ;
        RECT 15.000 82.280 33.200 83.120 ;
      LAYER met2 ;
        RECT 33.200 82.280 152.110 83.120 ;
      LAYER met2 ;
        RECT 15.000 81.440 32.920 82.280 ;
      LAYER met2 ;
        RECT 32.920 81.440 152.110 82.280 ;
      LAYER met2 ;
        RECT 15.000 80.600 32.640 81.440 ;
      LAYER met2 ;
        RECT 32.640 80.600 152.110 81.440 ;
      LAYER met2 ;
        RECT 15.000 79.480 32.360 80.600 ;
      LAYER met2 ;
        RECT 32.360 79.480 152.110 80.600 ;
      LAYER met2 ;
        RECT 15.000 78.640 32.080 79.480 ;
      LAYER met2 ;
        RECT 32.080 78.640 152.110 79.480 ;
      LAYER met2 ;
        RECT 15.000 78.080 31.800 78.640 ;
      LAYER met2 ;
        RECT 31.800 78.080 152.110 78.640 ;
      LAYER met2 ;
        RECT 15.000 77.240 31.520 78.080 ;
      LAYER met2 ;
        RECT 31.520 77.240 152.110 78.080 ;
      LAYER met2 ;
        RECT 15.000 76.120 31.240 77.240 ;
      LAYER met2 ;
        RECT 31.240 76.120 152.110 77.240 ;
      LAYER met2 ;
        RECT 15.000 75.280 30.960 76.120 ;
      LAYER met2 ;
        RECT 30.960 75.280 152.110 76.120 ;
      LAYER met2 ;
        RECT 15.000 74.440 30.680 75.280 ;
      LAYER met2 ;
        RECT 30.680 74.440 152.110 75.280 ;
      LAYER met2 ;
        RECT 15.000 73.320 30.400 74.440 ;
      LAYER met2 ;
        RECT 30.400 73.320 152.110 74.440 ;
      LAYER met2 ;
        RECT 15.000 72.480 30.120 73.320 ;
      LAYER met2 ;
        RECT 30.120 72.480 152.110 73.320 ;
      LAYER met2 ;
        RECT 15.000 71.920 29.840 72.480 ;
      LAYER met2 ;
        RECT 29.840 71.920 152.110 72.480 ;
      LAYER met2 ;
        RECT 15.000 71.080 29.560 71.920 ;
      LAYER met2 ;
        RECT 29.560 71.080 152.110 71.920 ;
      LAYER met2 ;
        RECT 15.000 70.240 29.280 71.080 ;
      LAYER met2 ;
        RECT 29.280 70.240 152.110 71.080 ;
      LAYER met2 ;
        RECT 15.000 69.400 29.000 70.240 ;
      LAYER met2 ;
        RECT 29.000 69.400 152.110 70.240 ;
      LAYER met2 ;
        RECT 15.000 68.840 28.720 69.400 ;
      LAYER met2 ;
        RECT 28.720 68.840 152.110 69.400 ;
      LAYER met2 ;
        RECT 15.000 68.000 28.440 68.840 ;
      LAYER met2 ;
        RECT 28.440 68.000 152.110 68.840 ;
      LAYER met2 ;
        RECT 15.000 67.160 28.160 68.000 ;
      LAYER met2 ;
        RECT 28.160 67.160 152.110 68.000 ;
      LAYER met2 ;
        RECT 15.000 66.320 27.880 67.160 ;
      LAYER met2 ;
        RECT 27.880 66.320 152.110 67.160 ;
      LAYER met2 ;
        RECT 15.000 65.760 27.600 66.320 ;
      LAYER met2 ;
        RECT 27.600 65.760 152.110 66.320 ;
      LAYER met2 ;
        RECT 15.000 64.920 27.320 65.760 ;
      LAYER met2 ;
        RECT 27.320 64.920 152.110 65.760 ;
      LAYER met2 ;
        RECT 15.000 64.360 27.040 64.920 ;
      LAYER met2 ;
        RECT 27.040 64.360 152.110 64.920 ;
      LAYER met2 ;
        RECT 15.000 63.800 26.760 64.360 ;
      LAYER met2 ;
        RECT 26.760 63.800 152.110 64.360 ;
      LAYER met2 ;
        RECT 15.000 62.960 26.480 63.800 ;
      LAYER met2 ;
        RECT 26.480 62.960 152.110 63.800 ;
      LAYER met2 ;
        RECT 15.000 62.120 26.200 62.960 ;
      LAYER met2 ;
        RECT 26.200 62.120 152.110 62.960 ;
      LAYER met2 ;
        RECT 15.000 61.560 25.920 62.120 ;
      LAYER met2 ;
        RECT 25.920 61.560 152.110 62.120 ;
      LAYER met2 ;
        RECT 15.000 61.000 25.640 61.560 ;
      LAYER met2 ;
        RECT 25.640 61.000 152.110 61.560 ;
      LAYER met2 ;
        RECT 15.000 60.160 25.360 61.000 ;
      LAYER met2 ;
        RECT 25.360 60.160 152.110 61.000 ;
      LAYER met2 ;
        RECT 15.000 59.600 25.080 60.160 ;
      LAYER met2 ;
        RECT 25.080 59.600 152.110 60.160 ;
      LAYER met2 ;
        RECT 15.000 59.040 24.800 59.600 ;
      LAYER met2 ;
        RECT 24.800 59.040 152.110 59.600 ;
      LAYER met2 ;
        RECT 15.000 58.200 24.520 59.040 ;
      LAYER met2 ;
        RECT 24.520 58.200 152.110 59.040 ;
      LAYER met2 ;
        RECT 15.000 57.360 24.240 58.200 ;
      LAYER met2 ;
        RECT 24.240 57.360 152.110 58.200 ;
      LAYER met2 ;
        RECT 15.000 56.800 23.960 57.360 ;
      LAYER met2 ;
        RECT 23.960 56.800 152.110 57.360 ;
      LAYER met2 ;
        RECT 15.000 56.240 23.680 56.800 ;
      LAYER met2 ;
        RECT 23.680 56.240 152.110 56.800 ;
      LAYER met2 ;
        RECT 15.000 55.120 23.400 56.240 ;
      LAYER met2 ;
        RECT 23.400 55.120 152.110 56.240 ;
      LAYER met2 ;
        RECT 15.000 54.560 23.120 55.120 ;
      LAYER met2 ;
        RECT 23.120 54.560 152.110 55.120 ;
      LAYER met2 ;
        RECT 15.000 54.000 22.840 54.560 ;
      LAYER met2 ;
        RECT 22.840 54.000 152.110 54.560 ;
      LAYER met2 ;
        RECT 15.000 53.160 22.560 54.000 ;
      LAYER met2 ;
        RECT 22.560 53.160 152.110 54.000 ;
      LAYER met2 ;
        RECT 15.000 52.600 22.280 53.160 ;
      LAYER met2 ;
        RECT 22.280 52.600 152.110 53.160 ;
      LAYER met2 ;
        RECT 15.000 51.760 22.000 52.600 ;
      LAYER met2 ;
        RECT 22.000 51.760 152.110 52.600 ;
      LAYER met2 ;
        RECT 15.000 51.200 21.720 51.760 ;
      LAYER met2 ;
        RECT 21.720 51.200 152.110 51.760 ;
      LAYER met2 ;
        RECT 15.000 50.920 21.440 51.200 ;
      LAYER met2 ;
        RECT 21.440 50.920 152.110 51.200 ;
      LAYER met2 ;
        RECT 15.000 50.360 21.160 50.920 ;
      LAYER met2 ;
        RECT 21.160 50.360 152.110 50.920 ;
      LAYER met2 ;
        RECT 15.000 49.800 20.880 50.360 ;
      LAYER met2 ;
        RECT 20.880 49.800 152.110 50.360 ;
      LAYER met2 ;
        RECT 15.000 49.520 20.600 49.800 ;
      LAYER met2 ;
        RECT 20.600 49.520 152.110 49.800 ;
      LAYER met2 ;
        RECT 15.000 48.960 20.320 49.520 ;
      LAYER met2 ;
        RECT 20.320 48.960 152.110 49.520 ;
      LAYER met2 ;
        RECT 15.000 48.400 20.040 48.960 ;
      LAYER met2 ;
        RECT 20.040 48.400 152.110 48.960 ;
      LAYER met2 ;
        RECT 15.000 48.120 19.760 48.400 ;
      LAYER met2 ;
        RECT 19.760 48.120 152.110 48.400 ;
      LAYER met2 ;
        RECT 15.000 47.560 19.480 48.120 ;
      LAYER met2 ;
        RECT 19.480 47.560 152.110 48.120 ;
      LAYER met2 ;
        RECT 15.000 46.720 19.200 47.560 ;
      LAYER met2 ;
        RECT 19.200 46.720 152.110 47.560 ;
      LAYER met2 ;
        RECT 15.000 46.160 18.920 46.720 ;
      LAYER met2 ;
        RECT 18.920 46.160 152.110 46.720 ;
      LAYER met2 ;
        RECT 15.000 45.880 18.640 46.160 ;
      LAYER met2 ;
        RECT 18.640 45.880 152.110 46.160 ;
      LAYER met2 ;
        RECT 15.000 45.040 18.360 45.880 ;
      LAYER met2 ;
        RECT 18.360 45.040 152.110 45.880 ;
      LAYER met2 ;
        RECT 15.000 44.200 18.080 45.040 ;
      LAYER met2 ;
        RECT 18.080 44.200 152.110 45.040 ;
      LAYER met2 ;
        RECT 15.000 43.640 17.800 44.200 ;
      LAYER met2 ;
        RECT 17.800 43.640 152.110 44.200 ;
      LAYER met2 ;
        RECT 15.000 43.080 17.520 43.640 ;
      LAYER met2 ;
        RECT 17.520 43.080 152.110 43.640 ;
      LAYER met2 ;
        RECT 15.000 41.400 17.240 43.080 ;
      LAYER met2 ;
        RECT 17.240 41.400 152.110 43.080 ;
      LAYER met2 ;
        RECT 15.000 40.560 16.960 41.400 ;
      LAYER met2 ;
        RECT 16.960 40.560 152.110 41.400 ;
      LAYER met2 ;
        RECT 15.000 39.440 16.680 40.560 ;
      LAYER met2 ;
        RECT 16.680 39.440 152.110 40.560 ;
      LAYER met2 ;
        RECT 15.000 37.760 16.400 39.440 ;
      LAYER met2 ;
        RECT 16.400 37.760 152.110 39.440 ;
      LAYER met2 ;
        RECT 15.000 35.240 16.120 37.760 ;
      LAYER met2 ;
        RECT 16.120 35.240 152.110 37.760 ;
      LAYER met2 ;
        RECT 15.000 31.880 15.840 35.240 ;
      LAYER met2 ;
        RECT 15.840 31.880 152.110 35.240 ;
      LAYER met2 ;
        RECT 15.000 29.640 16.120 31.880 ;
      LAYER met2 ;
        RECT 16.120 29.640 152.110 31.880 ;
      LAYER met2 ;
        RECT 15.000 28.240 16.400 29.640 ;
      LAYER met2 ;
        RECT 16.400 28.240 152.110 29.640 ;
      LAYER met2 ;
        RECT 15.000 27.680 16.680 28.240 ;
      LAYER met2 ;
        RECT 16.680 27.680 152.110 28.240 ;
      LAYER met2 ;
        RECT 15.000 27.120 16.960 27.680 ;
      LAYER met2 ;
        RECT 16.960 27.120 152.110 27.680 ;
      LAYER met2 ;
        RECT 15.000 26.560 17.240 27.120 ;
      LAYER met2 ;
        RECT 17.240 26.560 152.110 27.120 ;
      LAYER met2 ;
        RECT 15.000 26.000 17.520 26.560 ;
      LAYER met2 ;
        RECT 17.520 26.000 152.110 26.560 ;
      LAYER met2 ;
        RECT 15.000 25.720 17.800 26.000 ;
      LAYER met2 ;
        RECT 17.800 25.720 152.110 26.000 ;
      LAYER met2 ;
        RECT 15.000 25.440 18.080 25.720 ;
      LAYER met2 ;
        RECT 18.080 25.440 152.110 25.720 ;
      LAYER met2 ;
        RECT 15.000 25.160 18.360 25.440 ;
      LAYER met2 ;
        RECT 18.360 25.160 152.110 25.440 ;
      LAYER met2 ;
        RECT 15.000 24.600 18.640 25.160 ;
      LAYER met2 ;
        RECT 18.640 24.600 152.110 25.160 ;
      LAYER met2 ;
        RECT 15.000 24.320 18.920 24.600 ;
      LAYER met2 ;
        RECT 18.920 24.320 152.110 24.600 ;
      LAYER met2 ;
        RECT 15.000 24.040 19.200 24.320 ;
      LAYER met2 ;
        RECT 19.200 24.040 152.110 24.320 ;
      LAYER met2 ;
        RECT 15.000 23.760 19.480 24.040 ;
      LAYER met2 ;
        RECT 19.480 23.760 152.110 24.040 ;
      LAYER met2 ;
        RECT 15.000 23.480 19.760 23.760 ;
      LAYER met2 ;
        RECT 19.760 23.480 152.110 23.760 ;
      LAYER met2 ;
        RECT 15.000 23.200 20.040 23.480 ;
      LAYER met2 ;
        RECT 20.040 23.200 152.110 23.480 ;
      LAYER met2 ;
        RECT 15.000 22.920 20.320 23.200 ;
      LAYER met2 ;
        RECT 20.320 22.920 152.110 23.200 ;
      LAYER met2 ;
        RECT 15.000 22.640 20.600 22.920 ;
      LAYER met2 ;
        RECT 20.600 22.640 152.110 22.920 ;
      LAYER met2 ;
        RECT 15.000 22.360 21.160 22.640 ;
      LAYER met2 ;
        RECT 21.160 22.360 152.110 22.640 ;
      LAYER met2 ;
        RECT 15.000 22.080 21.440 22.360 ;
      LAYER met2 ;
        RECT 21.440 22.080 152.110 22.360 ;
      LAYER met2 ;
        RECT 15.000 21.800 21.720 22.080 ;
      LAYER met2 ;
        RECT 21.720 21.800 152.110 22.080 ;
      LAYER met2 ;
        RECT 15.000 21.520 22.000 21.800 ;
      LAYER met2 ;
        RECT 22.000 21.520 152.110 21.800 ;
      LAYER met2 ;
        RECT 15.000 21.240 22.280 21.520 ;
      LAYER met2 ;
        RECT 22.280 21.240 152.110 21.520 ;
      LAYER met2 ;
        RECT 15.000 20.960 22.840 21.240 ;
      LAYER met2 ;
        RECT 22.840 20.960 152.110 21.240 ;
      LAYER met2 ;
        RECT 15.000 20.680 23.400 20.960 ;
      LAYER met2 ;
        RECT 23.400 20.680 152.110 20.960 ;
      LAYER met2 ;
        RECT 15.000 20.400 24.800 20.680 ;
      LAYER met2 ;
        RECT 24.800 20.400 152.110 20.680 ;
      LAYER met2 ;
        RECT 15.000 13.680 26.480 20.400 ;
      LAYER met2 ;
        RECT 26.480 13.680 152.110 20.400 ;
      LAYER met2 ;
        RECT 15.000 12.560 26.760 13.680 ;
      LAYER met2 ;
        RECT 26.760 12.560 152.110 13.680 ;
      LAYER met2 ;
        RECT 15.000 12.280 27.040 12.560 ;
      LAYER met2 ;
        RECT 27.040 12.280 152.110 12.560 ;
      LAYER met2 ;
        RECT 15.000 11.720 27.320 12.280 ;
      LAYER met2 ;
        RECT 27.320 11.720 152.110 12.280 ;
      LAYER met2 ;
        RECT 15.000 11.440 28.160 11.720 ;
      LAYER met2 ;
        RECT 28.160 11.440 152.110 11.720 ;
      LAYER met2 ;
        RECT 15.000 11.160 81.640 11.440 ;
      LAYER met2 ;
        RECT 81.640 11.160 152.110 11.440 ;
      LAYER met2 ;
        RECT 15.000 10.040 81.360 11.160 ;
      LAYER met2 ;
        RECT 81.360 10.040 152.110 11.160 ;
      LAYER met2 ;
        RECT 15.000 8.640 81.080 10.040 ;
      LAYER met2 ;
        RECT 81.080 8.640 152.110 10.040 ;
      LAYER met2 ;
        RECT 15.000 7.800 81.360 8.640 ;
      LAYER met2 ;
        RECT 81.360 7.800 152.110 8.640 ;
      LAYER met2 ;
        RECT 15.000 7.240 81.640 7.800 ;
      LAYER met2 ;
        RECT 81.640 7.240 152.110 7.800 ;
      LAYER met2 ;
        RECT 15.000 6.960 81.920 7.240 ;
      LAYER met2 ;
        RECT 81.920 6.960 152.110 7.240 ;
      LAYER met2 ;
        RECT 15.000 6.680 82.480 6.960 ;
      LAYER met2 ;
        RECT 82.480 6.680 152.110 6.960 ;
      LAYER met2 ;
        RECT 15.000 6.400 83.320 6.680 ;
      LAYER met2 ;
        RECT 83.320 6.400 152.110 6.680 ;
      LAYER met2 ;
        RECT 15.000 6.120 120.560 6.400 ;
      LAYER met2 ;
        RECT 120.560 6.120 152.110 6.400 ;
      LAYER met2 ;
        RECT 15.000 5.840 121.120 6.120 ;
      LAYER met2 ;
        RECT 121.120 5.840 152.110 6.120 ;
      LAYER met2 ;
        RECT 15.000 5.000 130.360 5.840 ;
      LAYER met2 ;
        RECT 130.360 5.000 152.110 5.840 ;
        RECT 15.000 2.535 152.110 5.000 ;
      LAYER met3 ;
        RECT 15.000 98.800 152.130 111.345 ;
      LAYER met3 ;
        RECT 15.000 5.000 130.360 98.800 ;
      LAYER met3 ;
        RECT 130.360 5.000 152.130 98.800 ;
        RECT 15.000 2.555 152.130 5.000 ;
      LAYER met4 ;
        RECT 15.000 110.120 30.270 110.665 ;
        RECT 31.370 110.120 33.030 110.665 ;
        RECT 34.130 110.120 35.790 110.665 ;
        RECT 36.890 110.120 38.550 110.665 ;
        RECT 39.650 110.120 41.310 110.665 ;
        RECT 42.410 110.120 44.070 110.665 ;
        RECT 45.170 110.120 46.830 110.665 ;
        RECT 47.930 110.120 49.590 110.665 ;
        RECT 50.690 110.120 52.350 110.665 ;
        RECT 53.450 110.120 55.110 110.665 ;
        RECT 56.210 110.120 57.870 110.665 ;
        RECT 58.970 110.120 60.630 110.665 ;
        RECT 61.730 110.120 63.390 110.665 ;
        RECT 64.490 110.120 66.150 110.665 ;
        RECT 67.250 110.120 68.910 110.665 ;
        RECT 70.010 110.120 71.670 110.665 ;
        RECT 72.770 110.120 74.430 110.665 ;
        RECT 75.530 110.120 77.190 110.665 ;
        RECT 78.290 110.120 79.950 110.665 ;
        RECT 81.050 110.120 82.710 110.665 ;
        RECT 83.810 110.120 85.470 110.665 ;
        RECT 86.570 110.120 88.230 110.665 ;
        RECT 89.330 110.120 90.990 110.665 ;
        RECT 92.090 110.120 93.750 110.665 ;
        RECT 94.850 110.120 96.510 110.665 ;
        RECT 97.610 110.120 99.270 110.665 ;
        RECT 100.370 110.120 102.030 110.665 ;
        RECT 103.130 110.120 104.790 110.665 ;
        RECT 105.890 110.120 107.550 110.665 ;
        RECT 108.650 110.120 110.310 110.665 ;
        RECT 111.410 110.120 113.070 110.665 ;
        RECT 114.170 110.120 115.830 110.665 ;
        RECT 116.930 110.120 118.590 110.665 ;
        RECT 119.690 110.120 121.350 110.665 ;
        RECT 122.450 110.120 124.110 110.665 ;
        RECT 125.210 110.120 126.870 110.665 ;
        RECT 127.970 110.120 129.630 110.665 ;
        RECT 15.000 5.000 130.360 110.120 ;
  END
END tt_um_krisjdev_artwork
END LIBRARY

